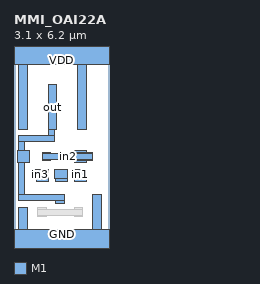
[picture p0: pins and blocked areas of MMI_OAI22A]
MACRO MMI_OAI22A
	CLASS CORE ;
	FOREIGN MMI_OAI22A 0 0 ;
	SIZE 3.1 BY 6.2 ;
	SYMMETRY X Y ;
	SITE CORE1 ;
	PIN out
		DIRECTION output ;
		USE SIGNAL ;
		PORT
			LAYER M1 ;
			RECT 1.12 3.67 1.4 5.14 ;
			LAYER M1 ;
			RECT 1.12 3.465 1.31 3.67 ;
			LAYER M1 ;
			RECT 0.15 3.27 1.31 3.465 ;
			LAYER M1 ;
			RECT 0.15 2.98 0.345 3.27 ;
			LAYER M1 ;
			RECT 0.12 2.6 0.5 2.98 ;
			LAYER M1 ;
			RECT 0.15 1.54 0.345 2.6 ;
			LAYER M1 ;
			RECT 0.15 1.35 1.645 1.54 ;
			LAYER M1 ;
			RECT 1.365 1.26 1.645 1.35 ;
		END
		AntennaDiffArea 1.0241 ;
	END out
	PIN in1
		DIRECTION input ;
		USE SIGNAL ;
		PORT
			LAYER M1 ;
			RECT 1.98 2.35 2.36 2.36 ;
			LAYER M1 ;
			RECT 1.945 2.07 2.36 2.35 ;
			LAYER M1 ;
			RECT 1.98 1.98 2.36 2.07 ;
		END
		AntennaGateArea 0.3465 ;
	END in1
	PIN GND
		DIRECTION inout ;
		USE GROUND ;
		PORT
			LAYER M1 ;
			RECT 0.16 0.42 0.44 1.12 ;
			LAYER M1 ;
			RECT 2.56 0.42 2.84 1.54 ;
			LAYER M1 ;
			RECT 0 -0.42 3.1 0.42 ;
		END
	END GND
	PIN in2
		DIRECTION input ;
		USE SIGNAL ;
		PORT
			LAYER M1 ;
			RECT 1.98 2.93 2.36 2.98 ;
			LAYER M1 ;
			RECT 0.925 2.885 1.205 2.93 ;
			LAYER M1 ;
			RECT 1.98 2.885 2.57 2.93 ;
			LAYER M1 ;
			RECT 0.925 2.695 2.57 2.885 ;
			LAYER M1 ;
			RECT 0.925 2.65 1.205 2.695 ;
			LAYER M1 ;
			RECT 1.98 2.65 2.57 2.695 ;
			LAYER M1 ;
			RECT 1.98 2.6 2.36 2.65 ;
		END
		AntennaGateArea 0.3465 ;
	END in2
	PIN VDD
		DIRECTION inout ;
		USE POWER ;
		PORT
			LAYER M1 ;
			RECT 0 5.78 3.1 6.62 ;
			LAYER M1 ;
			RECT 0.16 3.67 0.44 5.78 ;
			LAYER M1 ;
			RECT 2.08 3.67 2.36 5.78 ;
		END
	END VDD
	PIN in3
		DIRECTION input ;
		USE SIGNAL ;
		PORT
			LAYER M1 ;
			RECT 0.74 2.35 1.12 2.36 ;
			LAYER M1 ;
			RECT 0.555 2.07 1.12 2.35 ;
			LAYER M1 ;
			RECT 0.74 1.98 1.12 2.07 ;
		END
		AntennaGateArea 0.3465 ;
	END in3
	PIN in0
		DIRECTION input ;
		USE SIGNAL ;
		PORT
			LAYER M1 ;
			RECT 1.36 2.35 1.74 2.36 ;
			LAYER M1 ;
			RECT 1.32 2.07 1.74 2.35 ;
			LAYER M1 ;
			RECT 1.36 1.98 1.74 2.07 ;
		END
		AntennaGateArea 0.3465 ;
	END in0
	OBS
		LAYER M1 ;
		RECT 0.765 1.055 1.045 1.12 ;
		LAYER M1 ;
		RECT 1.97 1.055 2.25 1.12 ;
		LAYER M1 ;
		RECT 0.765 0.86 2.25 1.055 ;
		LAYER M1 ;
		RECT 0.765 0.84 1.045 0.86 ;
		LAYER M1 ;
		RECT 1.97 0.84 2.25 0.86 ;
	END
END MMI_OAI22A
